VERSION 5.8 ; BUSBITCHARS "[]" ; DIVIDERCHAR "/" ;
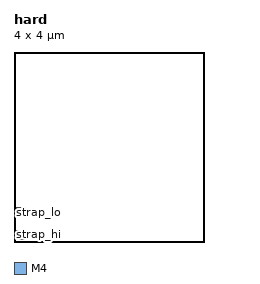
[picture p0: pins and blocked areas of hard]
MACRO hard CLASS BLOCK ; ORIGIN 0 0 ; SIZE 4 BY 4 ; SYMMETRY X Y ;
PIN strap_hi DIRECTION INPUT ; USE SIGNAL ; PORT LAYER M4 ; RECT 0.048 0.048 0.24 0.24 ; END END strap_hi
PIN strap_lo DIRECTION INPUT ; USE SIGNAL ; PORT LAYER M4 ; RECT 0.048 0.528 0.24 0.72 ; END END strap_lo
END hard END LIBRARY
